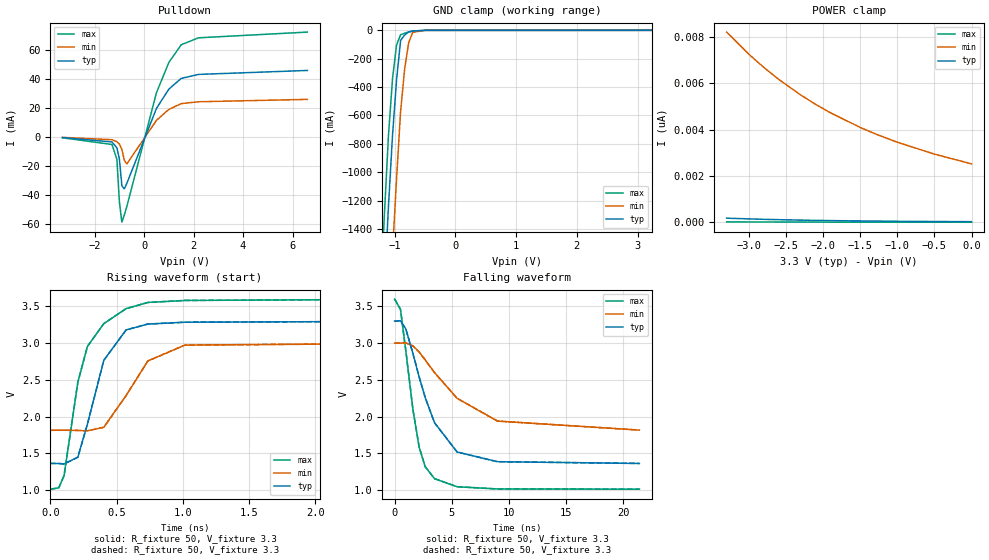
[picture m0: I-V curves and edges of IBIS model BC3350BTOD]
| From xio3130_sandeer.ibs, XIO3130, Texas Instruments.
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|**********************BC3350BTOD*********************************
|Since buffer is an Open drain,pullup data is not present.
|   Model Cell BC3350BTOD
|BC3350BTOD
[Model]   BC3350BTOD
Model_type   I/O_open_drain
Polarity   Non-Inverting
Enable   Active-Low
Vinl =  0.8V
Vinh =  2V
Cref =  15pF
Rref =  100.00M
Vref =  0V
Vmeas =  1.65
C_comp   1.713702p   1.614302p   1.870299p
[Model Spec]
Vinl   0.8V   0.8V   0.8V
Vinh   2V   2V   2V
[Temperature Range]   25   125   -40
[Voltage Range]   3.3   3   3.6
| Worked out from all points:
|   slope of the pulldown table from 0 to 0.495 V, typ, clamps not added: 25.5 ohm
|   GND clamp passes 1 mA (typ) near -0.58 V on its own axis
|   rising waveform, R_fixture 50, V_fixture 3.3: 20-80 % time 180ps typ, 241ps min, 181ps max; typ from 1.36 V to 3.3 V
|   rising waveform, R_fixture 50, V_fixture 3.3: 20-80 % time 180ps typ, 241ps min, 181ps max; typ from 1.36 V to 3.3 V
|   falling waveform, R_fixture 50, V_fixture 3.3: 20-80 % time 2.53ns typ, 4.5ns min, 1.39ns max; typ from 3.3 V to 1.36 V
|   falling waveform, R_fixture 50, V_fixture 3.3: 20-80 % time 2.53ns typ, 4.5ns min, 1.39ns max; typ from 3.3 V to 1.36 V
[POWER_clamp]
|   voltage   I(typ)   I(min)   I(max)
-3.3V     174.5pA    8.204nA    14.95pA
-3V       142.6pA    7.246nA    10.97pA
-2.8V     124.8pA    6.68nA     8.793pA
-2.6V     109pA      6.167nA    7.008pA
-2.3V     89.66pA    5.485nA    5.151pA
-2.1V     78.83pA    5.084nA    4.29pA
-1.9V     69.27pA    4.72nA     3.348pA
-1.5V     54pA       4.089nA    2.167pA
-1.3V     47.67pA    3.815nA    1.759pA
-1V       39.91pA    3.45nA     1.394pA
-500mV    29.7pA     2.938nA    817.1fA
-11.55fV  22.37pA    2.518nA    492.9fA
[Pulldown]
|   voltage   I(typ)   I(min)   I(max)
-3.3V     -518.9uA   -373uA     -640.2uA
-1.3V     -3.513mA   -1.974mA   -5.27mA
-1.1V     -7.628mA   -3.354mA   -15.48mA
-1V       -15.31mA   -4.99mA    -44.87mA
-900mV    -33.65mA   -8.703mA   -58.75mA
-800mV    -35.8mA    -16.15mA   -53.69mA
-700mV    -32.03mA   -18.66mA   -47.99mA
500mV     19.61mA    11.36mA    30.43mA
1V        32.82mA    18.89mA    51.18mA
1.5V      40.2mA     22.85mA    63.37mA
2.2V      42.96mA    24.13mA    68.15mA
6.6V      45.69mA    25.78mA    72.09mA
[GND_clamp]
|   voltage   I(typ)   I(min)   I(max)
-3.3V     -22.49A    -23.29A    -22.05A
-1.233V   -2.408A    -3.3A      -1.886A
-1.167V   -1.819A    -2.704A    -1.304A
-1.1V     -1.244A    -2.117A    -743.7mA
-1.033V   -742.4mA   -1.565A    -341.7mA
-966.7mV  -351.5mA   -1.05A     -104.1mA
-900mV    -71.26mA   -572.3mA   -30.76mA
-833.3mV  -33.08mA   -272.7mA   -20.38mA
-766.7mV  -10.99mA   -86.62mA   -11.77mA
-700mV    -4.996mA   -13.99mA   -4.949mA
-500mV    -102.4uA   -379.5uA   -41.08uA
3.233V    21.56pA    2.705nA    340.5fA
[Ramp]
| variable   typ   min   max
dV/dt_f   1.168565/2.539797n   0.7153849/4.531417n   1.56079/1.39163n
dV/dt_r   0.112111/0.1987815n  80.74308m/0.2571924n  0.1272999/0.1618787n
R_load = 50
[Rising Waveform]
R_fixture = 50
V_fixture = 3.3
V_fixture_min = 3
V_fixture_max = 3.6
|   time   V(typ)   V(min)   V(max)
0s        1.362V     1.813V     1.012V
64ps      1.361V     1.814V     1.03V
104ps     1.355V     1.814V     1.196V
208ps     1.447V     1.811V     2.467V
280ps     1.895V     1.806V     2.953V
404ps     2.765V     1.854V     3.264V
572ps     3.178V     2.285V     3.468V
736ps     3.258V     2.756V     3.552V
1.016ns   3.283V     2.972V     3.579V
2.98ns    3.297V     2.997V     3.598V
[Rising Waveform]
R_fixture = 50
V_fixture = 3.3
V_fixture_min = 3
V_fixture_max = 3.6
|   time   V(typ)   V(min)   V(max)
0s        1.362V     1.813V     1.012V
64ps      1.361V     1.814V     1.03V
104ps     1.355V     1.814V     1.196V
208ps     1.447V     1.811V     2.467V
280ps     1.895V     1.806V     2.953V
404ps     2.765V     1.854V     3.264V
572ps     3.178V     2.285V     3.468V
736ps     3.258V     2.756V     3.552V
1.016ns   3.283V     2.972V     3.579V
2.98ns    3.297V     2.997V     3.598V
[Falling Waveform]
R_fixture = 50
V_fixture = 3.3
V_fixture_min = 3
V_fixture_max = 3.6
|   time   V(typ)   V(min)   V(max)
0s        3.3V       3V         3.6V
516ps     3.305V     3.001V     3.459V
980ps     3.193V     3.004V     2.897V
1.6ns     2.862V     2.963V     2.101V
2.144ns   2.542V     2.879V     1.587V
2.672ns   2.261V     2.773V     1.319V
3.492ns   1.917V     2.599V     1.155V
5.468ns   1.518V     2.249V     1.045V
8.996ns   1.386V     1.939V     1.015V
21.42ns   1.362V     1.816V     1.012V
[Falling Waveform]
R_fixture = 50
V_fixture = 3.3
V_fixture_min = 3
V_fixture_max = 3.6
|   time   V(typ)   V(min)   V(max)
0s        3.3V       3V         3.6V
516ps     3.305V     3.001V     3.459V
980ps     3.193V     3.004V     2.897V
1.6ns     2.862V     2.963V     2.101V
2.144ns   2.542V     2.879V     1.587V
2.672ns   2.261V     2.773V     1.319V
3.492ns   1.917V     2.599V     1.155V
5.468ns   1.518V     2.249V     1.045V
8.996ns   1.386V     1.939V     1.015V
21.42ns   1.362V     1.816V     1.012V
